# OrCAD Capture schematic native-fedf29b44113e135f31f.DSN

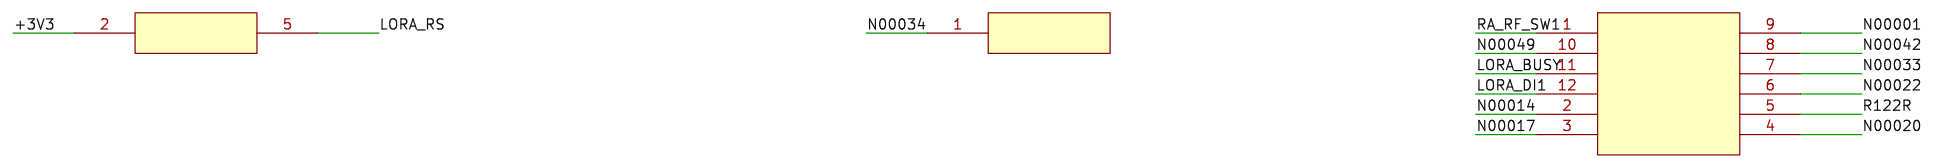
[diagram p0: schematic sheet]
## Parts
R1  10K
R31  22R
U1  Wio-SX1262

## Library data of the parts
R1 = OBS_R1
R31 = OBS_R31
U1 = OBS_U1

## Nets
+3V3: R1.2
LORA_BUSY: U1.11
LORA_DI1: U1.12
LORA_RS: R1.5
R122R: U1.5
RA_RF_SW1: U1.1

Not connected (* = marked no-connect by the designer): R31 1; U1 2 3 4 6 7 8 9 10
